VERSION 5.7 ;
  NOWIREEXTENSIONATPIN ON ;
  DIVIDERCHAR "/" ;
  BUSBITCHARS "[]" ;
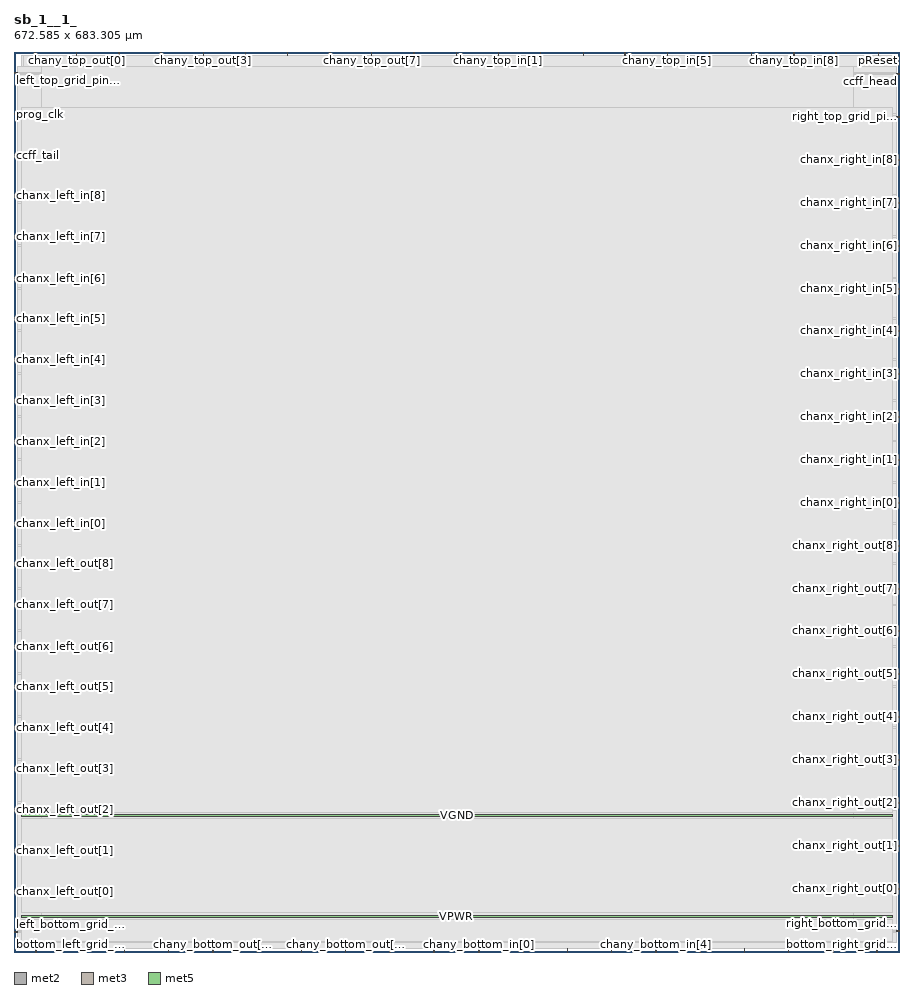
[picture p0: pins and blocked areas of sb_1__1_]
MACRO sb_1__1_
  CLASS BLOCK ;
  FOREIGN sb_1__1_ ;
  ORIGIN 0.000 0.000 ;
  SIZE 672.585 BY 683.305 ;
  PIN bottom_left_grid_pin_13_
    DIRECTION INPUT ;
    PORT
      LAYER met2 ;
        RECT 16.650 0.000 16.930 2.400 ;
    END
  END bottom_left_grid_pin_13_
  PIN bottom_right_grid_pin_11_
    DIRECTION INPUT ;
    PORT
      LAYER met2 ;
        RECT 655.130 0.000 655.410 2.400 ;
    END
  END bottom_right_grid_pin_11_
  PIN ccff_head
    DIRECTION INPUT ;
    PORT
      LAYER met3 ;
        RECT 670.185 666.440 672.585 667.040 ;
    END
  END ccff_head
  PIN ccff_tail
    DIRECTION OUTPUT TRISTATE ;
    PORT
      LAYER met3 ;
        RECT 0.000 604.560 2.400 605.160 ;
    END
  END ccff_tail
  PIN chanx_left_in[0]
    DIRECTION INPUT ;
    PORT
      LAYER met3 ;
        RECT 0.000 325.080 2.400 325.680 ;
    END
  END chanx_left_in[0]
  PIN chanx_left_in[1]
    DIRECTION INPUT ;
    PORT
      LAYER met3 ;
        RECT 0.000 356.360 2.400 356.960 ;
    END
  END chanx_left_in[1]
  PIN chanx_left_in[2]
    DIRECTION INPUT ;
    PORT
      LAYER met3 ;
        RECT 0.000 387.640 2.400 388.240 ;
    END
  END chanx_left_in[2]
  PIN chanx_left_in[3]
    DIRECTION INPUT ;
    PORT
      LAYER met3 ;
        RECT 0.000 418.240 2.400 418.840 ;
    END
  END chanx_left_in[3]
  PIN chanx_left_in[4]
    DIRECTION INPUT ;
    PORT
      LAYER met3 ;
        RECT 0.000 449.520 2.400 450.120 ;
    END
  END chanx_left_in[4]
  PIN chanx_left_in[5]
    DIRECTION INPUT ;
    PORT
      LAYER met3 ;
        RECT 0.000 480.800 2.400 481.400 ;
    END
  END chanx_left_in[5]
  PIN chanx_left_in[6]
    DIRECTION INPUT ;
    PORT
      LAYER met3 ;
        RECT 0.000 511.400 2.400 512.000 ;
    END
  END chanx_left_in[6]
  PIN chanx_left_in[7]
    DIRECTION INPUT ;
    PORT
      LAYER met3 ;
        RECT 0.000 542.680 2.400 543.280 ;
    END
  END chanx_left_in[7]
  PIN chanx_left_in[8]
    DIRECTION INPUT ;
    PORT
      LAYER met3 ;
        RECT 0.000 573.960 2.400 574.560 ;
    END
  END chanx_left_in[8]
  PIN chanx_left_out[0]
    DIRECTION OUTPUT TRISTATE ;
    PORT
      LAYER met3 ;
        RECT 0.000 45.600 2.400 46.200 ;
    END
  END chanx_left_out[0]
  PIN chanx_left_out[1]
    DIRECTION OUTPUT TRISTATE ;
    PORT
      LAYER met3 ;
        RECT 0.000 76.880 2.400 77.480 ;
    END
  END chanx_left_out[1]
  PIN chanx_left_out[2]
    DIRECTION OUTPUT TRISTATE ;
    PORT
      LAYER met3 ;
        RECT 0.000 108.160 2.400 108.760 ;
    END
  END chanx_left_out[2]
  PIN chanx_left_out[3]
    DIRECTION OUTPUT TRISTATE ;
    PORT
      LAYER met3 ;
        RECT 0.000 138.760 2.400 139.360 ;
    END
  END chanx_left_out[3]
  PIN chanx_left_out[4]
    DIRECTION OUTPUT TRISTATE ;
    PORT
      LAYER met3 ;
        RECT 0.000 170.040 2.400 170.640 ;
    END
  END chanx_left_out[4]
  PIN chanx_left_out[5]
    DIRECTION OUTPUT TRISTATE ;
    PORT
      LAYER met3 ;
        RECT 0.000 201.320 2.400 201.920 ;
    END
  END chanx_left_out[5]
  PIN chanx_left_out[6]
    DIRECTION OUTPUT TRISTATE ;
    PORT
      LAYER met3 ;
        RECT 0.000 231.920 2.400 232.520 ;
    END
  END chanx_left_out[6]
  PIN chanx_left_out[7]
    DIRECTION OUTPUT TRISTATE ;
    PORT
      LAYER met3 ;
        RECT 0.000 263.200 2.400 263.800 ;
    END
  END chanx_left_out[7]
  PIN chanx_left_out[8]
    DIRECTION OUTPUT TRISTATE ;
    PORT
      LAYER met3 ;
        RECT 0.000 294.480 2.400 295.080 ;
    END
  END chanx_left_out[8]
  PIN chanx_right_in[0]
    DIRECTION INPUT ;
    PORT
      LAYER met3 ;
        RECT 670.185 340.720 672.585 341.320 ;
    END
  END chanx_right_in[0]
  PIN chanx_right_in[1]
    DIRECTION INPUT ;
    PORT
      LAYER met3 ;
        RECT 670.185 373.360 672.585 373.960 ;
    END
  END chanx_right_in[1]
  PIN chanx_right_in[2]
    DIRECTION INPUT ;
    PORT
      LAYER met3 ;
        RECT 670.185 406.000 672.585 406.600 ;
    END
  END chanx_right_in[2]
  PIN chanx_right_in[3]
    DIRECTION INPUT ;
    PORT
      LAYER met3 ;
        RECT 670.185 438.640 672.585 439.240 ;
    END
  END chanx_right_in[3]
  PIN chanx_right_in[4]
    DIRECTION INPUT ;
    PORT
      LAYER met3 ;
        RECT 670.185 471.280 672.585 471.880 ;
    END
  END chanx_right_in[4]
  PIN chanx_right_in[5]
    DIRECTION INPUT ;
    PORT
      LAYER met3 ;
        RECT 670.185 503.240 672.585 503.840 ;
    END
  END chanx_right_in[5]
  PIN chanx_right_in[6]
    DIRECTION INPUT ;
    PORT
      LAYER met3 ;
        RECT 670.185 535.880 672.585 536.480 ;
    END
  END chanx_right_in[6]
  PIN chanx_right_in[7]
    DIRECTION INPUT ;
    PORT
      LAYER met3 ;
        RECT 670.185 568.520 672.585 569.120 ;
    END
  END chanx_right_in[7]
  PIN chanx_right_in[8]
    DIRECTION INPUT ;
    PORT
      LAYER met3 ;
        RECT 670.185 601.160 672.585 601.760 ;
    END
  END chanx_right_in[8]
  PIN chanx_right_out[0]
    DIRECTION OUTPUT TRISTATE ;
    PORT
      LAYER met3 ;
        RECT 670.185 47.640 672.585 48.240 ;
    END
  END chanx_right_out[0]
  PIN chanx_right_out[1]
    DIRECTION OUTPUT TRISTATE ;
    PORT
      LAYER met3 ;
        RECT 670.185 80.280 672.585 80.880 ;
    END
  END chanx_right_out[1]
  PIN chanx_right_out[2]
    DIRECTION OUTPUT TRISTATE ;
    PORT
      LAYER met3 ;
        RECT 670.185 112.920 672.585 113.520 ;
    END
  END chanx_right_out[2]
  PIN chanx_right_out[3]
    DIRECTION OUTPUT TRISTATE ;
    PORT
      LAYER met3 ;
        RECT 670.185 145.560 672.585 146.160 ;
    END
  END chanx_right_out[3]
  PIN chanx_right_out[4]
    DIRECTION OUTPUT TRISTATE ;
    PORT
      LAYER met3 ;
        RECT 670.185 178.200 672.585 178.800 ;
    END
  END chanx_right_out[4]
  PIN chanx_right_out[5]
    DIRECTION OUTPUT TRISTATE ;
    PORT
      LAYER met3 ;
        RECT 670.185 210.840 672.585 211.440 ;
    END
  END chanx_right_out[5]
  PIN chanx_right_out[6]
    DIRECTION OUTPUT TRISTATE ;
    PORT
      LAYER met3 ;
        RECT 670.185 243.480 672.585 244.080 ;
    END
  END chanx_right_out[6]
  PIN chanx_right_out[7]
    DIRECTION OUTPUT TRISTATE ;
    PORT
      LAYER met3 ;
        RECT 670.185 275.440 672.585 276.040 ;
    END
  END chanx_right_out[7]
  PIN chanx_right_out[8]
    DIRECTION OUTPUT TRISTATE ;
    PORT
      LAYER met3 ;
        RECT 670.185 308.080 672.585 308.680 ;
    END
  END chanx_right_out[8]
  PIN chany_bottom_in[0]
    DIRECTION INPUT ;
    PORT
      LAYER met2 ;
        RECT 352.910 0.000 353.190 2.400 ;
    END
  END chany_bottom_in[0]
  PIN chany_bottom_in[1]
    DIRECTION INPUT ;
    PORT
      LAYER met2 ;
        RECT 386.490 0.000 386.770 2.400 ;
    END
  END chany_bottom_in[1]
  PIN chany_bottom_in[2]
    DIRECTION INPUT ;
    PORT
      LAYER met2 ;
        RECT 420.070 0.000 420.350 2.400 ;
    END
  END chany_bottom_in[2]
  PIN chany_bottom_in[3]
    DIRECTION INPUT ;
    PORT
      LAYER met2 ;
        RECT 453.650 0.000 453.930 2.400 ;
    END
  END chany_bottom_in[3]
  PIN chany_bottom_in[4]
    DIRECTION INPUT ;
    PORT
      LAYER met2 ;
        RECT 487.230 0.000 487.510 2.400 ;
    END
  END chany_bottom_in[4]
  PIN chany_bottom_in[5]
    DIRECTION INPUT ;
    PORT
      LAYER met2 ;
        RECT 520.810 0.000 521.090 2.400 ;
    END
  END chany_bottom_in[5]
  PIN chany_bottom_in[6]
    DIRECTION INPUT ;
    PORT
      LAYER met2 ;
        RECT 554.390 0.000 554.670 2.400 ;
    END
  END chany_bottom_in[6]
  PIN chany_bottom_in[7]
    DIRECTION INPUT ;
    PORT
      LAYER met2 ;
        RECT 587.970 0.000 588.250 2.400 ;
    END
  END chany_bottom_in[7]
  PIN chany_bottom_in[8]
    DIRECTION INPUT ;
    PORT
      LAYER met2 ;
        RECT 621.550 0.000 621.830 2.400 ;
    END
  END chany_bottom_in[8]
  PIN chany_bottom_out[0]
    DIRECTION OUTPUT TRISTATE ;
    PORT
      LAYER met2 ;
        RECT 50.230 0.000 50.510 2.400 ;
    END
  END chany_bottom_out[0]
  PIN chany_bottom_out[1]
    DIRECTION OUTPUT TRISTATE ;
    PORT
      LAYER met2 ;
        RECT 83.810 0.000 84.090 2.400 ;
    END
  END chany_bottom_out[1]
  PIN chany_bottom_out[2]
    DIRECTION OUTPUT TRISTATE ;
    PORT
      LAYER met2 ;
        RECT 117.390 0.000 117.670 2.400 ;
    END
  END chany_bottom_out[2]
  PIN chany_bottom_out[3]
    DIRECTION OUTPUT TRISTATE ;
    PORT
      LAYER met2 ;
        RECT 150.970 0.000 151.250 2.400 ;
    END
  END chany_bottom_out[3]
  PIN chany_bottom_out[4]
    DIRECTION OUTPUT TRISTATE ;
    PORT
      LAYER met2 ;
        RECT 184.550 0.000 184.830 2.400 ;
    END
  END chany_bottom_out[4]
  PIN chany_bottom_out[5]
    DIRECTION OUTPUT TRISTATE ;
    PORT
      LAYER met2 ;
        RECT 218.130 0.000 218.410 2.400 ;
    END
  END chany_bottom_out[5]
  PIN chany_bottom_out[6]
    DIRECTION OUTPUT TRISTATE ;
    PORT
      LAYER met2 ;
        RECT 251.710 0.000 251.990 2.400 ;
    END
  END chany_bottom_out[6]
  PIN chany_bottom_out[7]
    DIRECTION OUTPUT TRISTATE ;
    PORT
      LAYER met2 ;
        RECT 285.290 0.000 285.570 2.400 ;
    END
  END chany_bottom_out[7]
  PIN chany_bottom_out[8]
    DIRECTION OUTPUT TRISTATE ;
    PORT
      LAYER met2 ;
        RECT 318.870 0.000 319.150 2.400 ;
    END
  END chany_bottom_out[8]
  PIN chany_top_in[0]
    DIRECTION INPUT ;
    PORT
      LAYER met2 ;
        RECT 335.890 680.905 336.170 683.305 ;
    END
  END chany_top_in[0]
  PIN chany_top_in[1]
    DIRECTION INPUT ;
    PORT
      LAYER met2 ;
        RECT 367.630 680.905 367.910 683.305 ;
    END
  END chany_top_in[1]
  PIN chany_top_in[2]
    DIRECTION INPUT ;
    PORT
      LAYER met2 ;
        RECT 399.830 680.905 400.110 683.305 ;
    END
  END chany_top_in[2]
  PIN chany_top_in[3]
    DIRECTION INPUT ;
    PORT
      LAYER met2 ;
        RECT 432.030 680.905 432.310 683.305 ;
    END
  END chany_top_in[3]
  PIN chany_top_in[4]
    DIRECTION INPUT ;
    PORT
      LAYER met2 ;
        RECT 463.770 680.905 464.050 683.305 ;
    END
  END chany_top_in[4]
  PIN chany_top_in[5]
    DIRECTION INPUT ;
    PORT
      LAYER met2 ;
        RECT 495.970 680.905 496.250 683.305 ;
    END
  END chany_top_in[5]
  PIN chany_top_in[6]
    DIRECTION INPUT ;
    PORT
      LAYER met2 ;
        RECT 527.710 680.905 527.990 683.305 ;
    END
  END chany_top_in[6]
  PIN chany_top_in[7]
    DIRECTION INPUT ;
    PORT
      LAYER met2 ;
        RECT 559.910 680.905 560.190 683.305 ;
    END
  END chany_top_in[7]
  PIN chany_top_in[8]
    DIRECTION INPUT ;
    PORT
      LAYER met2 ;
        RECT 592.110 680.905 592.390 683.305 ;
    END
  END chany_top_in[8]
  PIN chany_top_out[0]
    DIRECTION OUTPUT TRISTATE ;
    PORT
      LAYER met2 ;
        RECT 47.470 680.905 47.750 683.305 ;
    END
  END chany_top_out[0]
  PIN chany_top_out[1]
    DIRECTION OUTPUT TRISTATE ;
    PORT
      LAYER met2 ;
        RECT 79.670 680.905 79.950 683.305 ;
    END
  END chany_top_out[1]
  PIN chany_top_out[2]
    DIRECTION OUTPUT TRISTATE ;
    PORT
      LAYER met2 ;
        RECT 111.410 680.905 111.690 683.305 ;
    END
  END chany_top_out[2]
  PIN chany_top_out[3]
    DIRECTION OUTPUT TRISTATE ;
    PORT
      LAYER met2 ;
        RECT 143.610 680.905 143.890 683.305 ;
    END
  END chany_top_out[3]
  PIN chany_top_out[4]
    DIRECTION OUTPUT TRISTATE ;
    PORT
      LAYER met2 ;
        RECT 175.810 680.905 176.090 683.305 ;
    END
  END chany_top_out[4]
  PIN chany_top_out[5]
    DIRECTION OUTPUT TRISTATE ;
    PORT
      LAYER met2 ;
        RECT 207.550 680.905 207.830 683.305 ;
    END
  END chany_top_out[5]
  PIN chany_top_out[6]
    DIRECTION OUTPUT TRISTATE ;
    PORT
      LAYER met2 ;
        RECT 239.750 680.905 240.030 683.305 ;
    END
  END chany_top_out[6]
  PIN chany_top_out[7]
    DIRECTION OUTPUT TRISTATE ;
    PORT
      LAYER met2 ;
        RECT 271.490 680.905 271.770 683.305 ;
    END
  END chany_top_out[7]
  PIN chany_top_out[8]
    DIRECTION OUTPUT TRISTATE ;
    PORT
      LAYER met2 ;
        RECT 303.690 680.905 303.970 683.305 ;
    END
  END chany_top_out[8]
  PIN left_bottom_grid_pin_12_
    DIRECTION INPUT ;
    PORT
      LAYER met3 ;
        RECT 0.000 15.000 2.400 15.600 ;
    END
  END left_bottom_grid_pin_12_
  PIN left_top_grid_pin_10_
    DIRECTION INPUT ;
    PORT
      LAYER met3 ;
        RECT 0.000 667.120 2.400 667.720 ;
    END
  END left_top_grid_pin_10_
  PIN pReset
    DIRECTION INPUT ;
    PORT
      LAYER met2 ;
        RECT 656.050 680.905 656.330 683.305 ;
    END
  END pReset
  PIN prog_clk
    DIRECTION INPUT ;
    PORT
      LAYER met3 ;
        RECT 0.000 635.840 2.400 636.440 ;
    END
  END prog_clk
  PIN right_bottom_grid_pin_12_
    DIRECTION INPUT ;
    PORT
      LAYER met3 ;
        RECT 670.185 15.680 672.585 16.280 ;
    END
  END right_bottom_grid_pin_12_
  PIN right_top_grid_pin_10_
    DIRECTION INPUT ;
    PORT
      LAYER met3 ;
        RECT 670.185 633.800 672.585 634.400 ;
    END
  END right_top_grid_pin_10_
  PIN top_left_grid_pin_13_
    DIRECTION INPUT ;
    PORT
      LAYER met2 ;
        RECT 15.730 680.905 16.010 683.305 ;
    END
  END top_left_grid_pin_13_
  PIN top_right_grid_pin_11_
    DIRECTION INPUT ;
    PORT
      LAYER met2 ;
        RECT 623.850 680.905 624.130 683.305 ;
    END
  END top_right_grid_pin_11_
  PIN VPWR
    DIRECTION INPUT ;
    USE POWER ;
    PORT
      LAYER met5 ;
        RECT 5.520 26.490 667.000 28.090 ;
    END
  END VPWR
  PIN VGND
    DIRECTION INPUT ;
    USE GROUND ;
    PORT
      LAYER met5 ;
        RECT 5.520 103.080 667.000 104.680 ;
    END
  END VGND
  OBS
      LAYER li1 ;
        RECT 5.520 10.795 667.000 671.925 ;
      LAYER met1 ;
        RECT 5.520 10.640 667.000 680.640 ;
      LAYER met2 ;
        RECT 6.990 680.625 15.450 680.905 ;
        RECT 16.290 680.625 47.190 680.905 ;
        RECT 48.030 680.625 79.390 680.905 ;
        RECT 80.230 680.625 111.130 680.905 ;
        RECT 111.970 680.625 143.330 680.905 ;
        RECT 144.170 680.625 175.530 680.905 ;
        RECT 176.370 680.625 207.270 680.905 ;
        RECT 208.110 680.625 239.470 680.905 ;
        RECT 240.310 680.625 271.210 680.905 ;
        RECT 272.050 680.625 303.410 680.905 ;
        RECT 304.250 680.625 335.610 680.905 ;
        RECT 336.450 680.625 367.350 680.905 ;
        RECT 368.190 680.625 399.550 680.905 ;
        RECT 400.390 680.625 431.750 680.905 ;
        RECT 432.590 680.625 463.490 680.905 ;
        RECT 464.330 680.625 495.690 680.905 ;
        RECT 496.530 680.625 527.430 680.905 ;
        RECT 528.270 680.625 559.630 680.905 ;
        RECT 560.470 680.625 591.830 680.905 ;
        RECT 592.670 680.625 623.570 680.905 ;
        RECT 624.410 680.625 655.770 680.905 ;
        RECT 656.610 680.625 660.930 680.905 ;
        RECT 6.990 2.680 660.930 680.625 ;
        RECT 6.990 2.400 16.370 2.680 ;
        RECT 17.210 2.400 49.950 2.680 ;
        RECT 50.790 2.400 83.530 2.680 ;
        RECT 84.370 2.400 117.110 2.680 ;
        RECT 117.950 2.400 150.690 2.680 ;
        RECT 151.530 2.400 184.270 2.680 ;
        RECT 185.110 2.400 217.850 2.680 ;
        RECT 218.690 2.400 251.430 2.680 ;
        RECT 252.270 2.400 285.010 2.680 ;
        RECT 285.850 2.400 318.590 2.680 ;
        RECT 319.430 2.400 352.630 2.680 ;
        RECT 353.470 2.400 386.210 2.680 ;
        RECT 387.050 2.400 419.790 2.680 ;
        RECT 420.630 2.400 453.370 2.680 ;
        RECT 454.210 2.400 486.950 2.680 ;
        RECT 487.790 2.400 520.530 2.680 ;
        RECT 521.370 2.400 554.110 2.680 ;
        RECT 554.950 2.400 587.690 2.680 ;
        RECT 588.530 2.400 621.270 2.680 ;
        RECT 622.110 2.400 654.850 2.680 ;
        RECT 655.690 2.400 660.930 2.680 ;
      LAYER met3 ;
        RECT 2.400 668.120 670.185 672.005 ;
        RECT 2.800 667.440 670.185 668.120 ;
        RECT 2.800 666.720 669.785 667.440 ;
        RECT 2.400 666.040 669.785 666.720 ;
        RECT 2.400 636.840 670.185 666.040 ;
        RECT 2.800 635.440 670.185 636.840 ;
        RECT 2.400 634.800 670.185 635.440 ;
        RECT 2.400 633.400 669.785 634.800 ;
        RECT 2.400 605.560 670.185 633.400 ;
        RECT 2.800 604.160 670.185 605.560 ;
        RECT 2.400 602.160 670.185 604.160 ;
        RECT 2.400 600.760 669.785 602.160 ;
        RECT 2.400 574.960 670.185 600.760 ;
        RECT 2.800 573.560 670.185 574.960 ;
        RECT 2.400 569.520 670.185 573.560 ;
        RECT 2.400 568.120 669.785 569.520 ;
        RECT 2.400 543.680 670.185 568.120 ;
        RECT 2.800 542.280 670.185 543.680 ;
        RECT 2.400 536.880 670.185 542.280 ;
        RECT 2.400 535.480 669.785 536.880 ;
        RECT 2.400 512.400 670.185 535.480 ;
        RECT 2.800 511.000 670.185 512.400 ;
        RECT 2.400 504.240 670.185 511.000 ;
        RECT 2.400 502.840 669.785 504.240 ;
        RECT 2.400 481.800 670.185 502.840 ;
        RECT 2.800 480.400 670.185 481.800 ;
        RECT 2.400 472.280 670.185 480.400 ;
        RECT 2.400 470.880 669.785 472.280 ;
        RECT 2.400 450.520 670.185 470.880 ;
        RECT 2.800 449.120 670.185 450.520 ;
        RECT 2.400 439.640 670.185 449.120 ;
        RECT 2.400 438.240 669.785 439.640 ;
        RECT 2.400 419.240 670.185 438.240 ;
        RECT 2.800 417.840 670.185 419.240 ;
        RECT 2.400 407.000 670.185 417.840 ;
        RECT 2.400 405.600 669.785 407.000 ;
        RECT 2.400 388.640 670.185 405.600 ;
        RECT 2.800 387.240 670.185 388.640 ;
        RECT 2.400 374.360 670.185 387.240 ;
        RECT 2.400 372.960 669.785 374.360 ;
        RECT 2.400 357.360 670.185 372.960 ;
        RECT 2.800 355.960 670.185 357.360 ;
        RECT 2.400 341.720 670.185 355.960 ;
        RECT 2.400 340.320 669.785 341.720 ;
        RECT 2.400 326.080 670.185 340.320 ;
        RECT 2.800 324.680 670.185 326.080 ;
        RECT 2.400 309.080 670.185 324.680 ;
        RECT 2.400 307.680 669.785 309.080 ;
        RECT 2.400 295.480 670.185 307.680 ;
        RECT 2.800 294.080 670.185 295.480 ;
        RECT 2.400 276.440 670.185 294.080 ;
        RECT 2.400 275.040 669.785 276.440 ;
        RECT 2.400 264.200 670.185 275.040 ;
        RECT 2.800 262.800 670.185 264.200 ;
        RECT 2.400 244.480 670.185 262.800 ;
        RECT 2.400 243.080 669.785 244.480 ;
        RECT 2.400 232.920 670.185 243.080 ;
        RECT 2.800 231.520 670.185 232.920 ;
        RECT 2.400 211.840 670.185 231.520 ;
        RECT 2.400 210.440 669.785 211.840 ;
        RECT 2.400 202.320 670.185 210.440 ;
        RECT 2.800 200.920 670.185 202.320 ;
        RECT 2.400 179.200 670.185 200.920 ;
        RECT 2.400 177.800 669.785 179.200 ;
        RECT 2.400 171.040 670.185 177.800 ;
        RECT 2.800 169.640 670.185 171.040 ;
        RECT 2.400 146.560 670.185 169.640 ;
        RECT 2.400 145.160 669.785 146.560 ;
        RECT 2.400 139.760 670.185 145.160 ;
        RECT 2.800 138.360 670.185 139.760 ;
        RECT 2.400 113.920 670.185 138.360 ;
        RECT 2.400 112.520 669.785 113.920 ;
        RECT 2.400 109.160 670.185 112.520 ;
        RECT 2.800 107.760 670.185 109.160 ;
        RECT 2.400 81.280 670.185 107.760 ;
        RECT 2.400 79.880 669.785 81.280 ;
        RECT 2.400 77.880 670.185 79.880 ;
        RECT 2.800 76.480 670.185 77.880 ;
        RECT 2.400 48.640 670.185 76.480 ;
        RECT 2.400 47.240 669.785 48.640 ;
        RECT 2.400 46.600 670.185 47.240 ;
        RECT 2.800 45.200 670.185 46.600 ;
        RECT 2.400 16.680 670.185 45.200 ;
        RECT 2.400 16.000 669.785 16.680 ;
        RECT 2.800 15.280 669.785 16.000 ;
        RECT 2.800 14.600 670.185 15.280 ;
        RECT 2.400 6.975 670.185 14.600 ;
      LAYER met4 ;
        RECT 21.040 7.910 637.040 672.080 ;
      LAYER met5 ;
        RECT 5.520 106.280 667.000 640.810 ;
        RECT 5.520 29.690 667.000 101.480 ;
        RECT 5.520 7.700 667.000 24.890 ;
  END
END sb_1__1_
END LIBRARY

